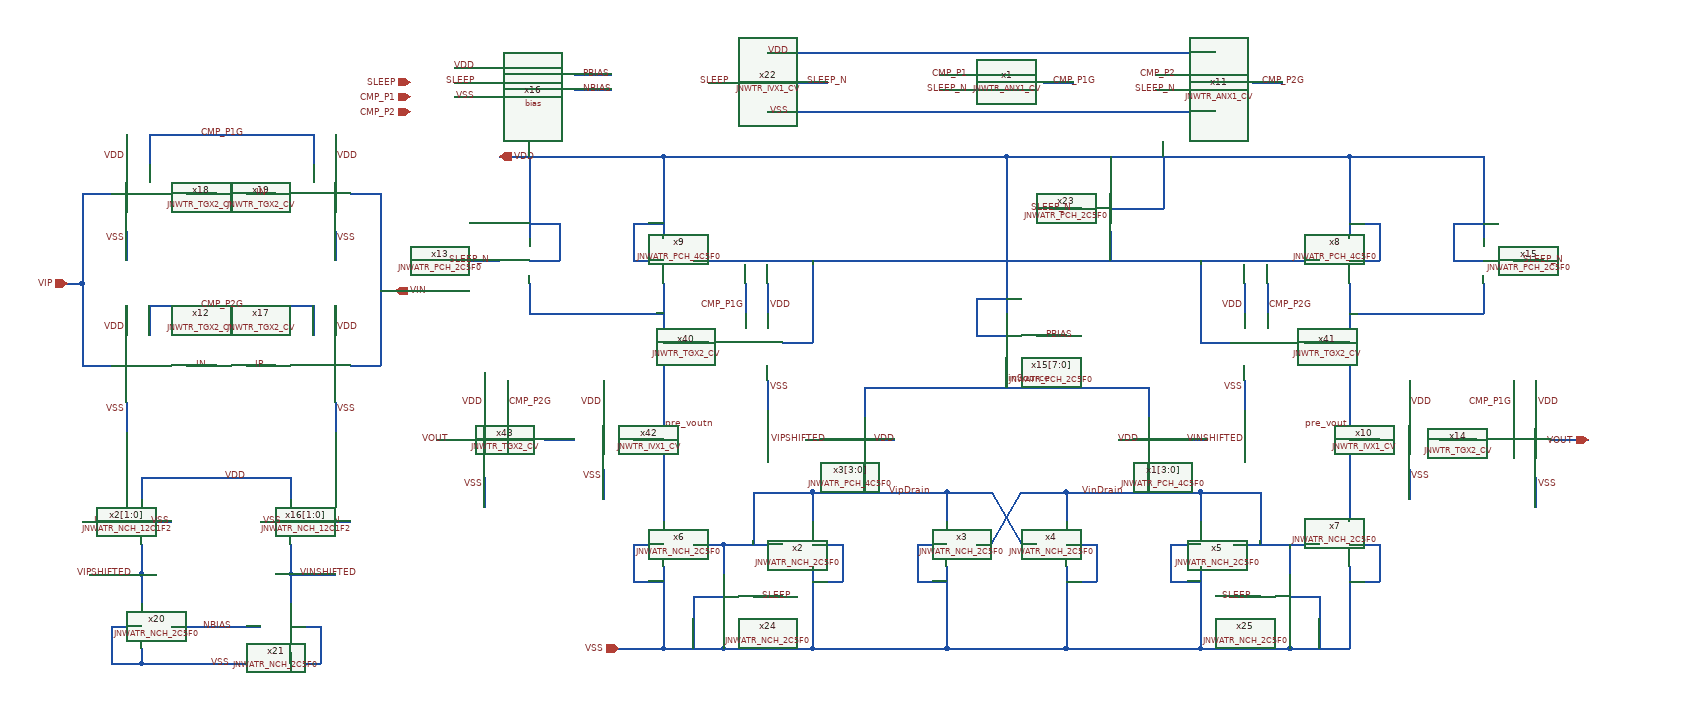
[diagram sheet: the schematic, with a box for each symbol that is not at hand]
v {xschem version=3.4.6 file_version=1.2}
G {}
K {}
V {}
S {}
E {}
N 1240 -550 1240 -510 {
lab=VipDrain}
N 1420 -550 1420 -510 {
lab=VipDrain}
N 1580 -550 1580 -510 {
lab=VinDrain}
N 1680 -550 1760 -550 {
lab=VinDrain}
N 1460 -480 1480 -480 {
lab=VinDrain}
N 1480 -480 1520 -550 {
lab=VinDrain}
N 1520 -480 1540 -480 {
lab=VipDrain}
N 1480 -550 1520 -480 {
lab=VipDrain}
N 1420 -550 1480 -550 {
lab=VipDrain}
N 1520 -550 1580 -550 {
lab=VinDrain}
N 1160 -550 1240 -550 {
lab=VipDrain}
N 1160 -550 1160 -480 {
lab=VipDrain}
N 1240 -860 1240 -750 {
lab=#net1}
N 1730 -1000 1960 -1000 {
lab=VDD}
N 1880 -340 1960 -340 {
lab=VSS}
N 1310 -690 1310 -650 {
lab=inSource}
N 1690 -690 1690 -650 {
lab=inSource}
N 2180 -700 2180 -660 {
lab=CMP_P1G}
N 2230 -620 2280 -620 {
lab=VOUT}
N 260 -830 260 -720 {
lab=VIP}
N 260 -950 300 -950 {
lab=VIP}
N 260 -720 300 -720 {
lab=VIP}
N 660 -950 660 -720 {
lab=VIN}
N 620 -950 660 -950 {
lab=VIN}
N 620 -720 660 -720 {
lab=VIN}
N 350 -800 350 -760 {
lab=CMP_P2G}
N 350 -800 570 -800 {
lab=CMP_P2G}
N 570 -800 570 -760 {
lab=CMP_P2G}
N 350 -1030 350 -990 {
lab=CMP_P1G}
N 350 -1030 570 -1030 {
lab=CMP_P1G}
N 570 -1030 570 -990 {
lab=CMP_P1G}
N 1230 -620 1270 -620 {lab=VIPSHIFTED}
N 260 -950 260 -830 {
lab=VIP}
N 1730 -620 1770 -620 {lab=VINSHIFTED}
N 1580 -550 1680 -550 {
lab=VinDrain}
N 1240 -550 1420 -550 {
lab=VipDrain}
N 1540 -760 1580 -760 {lab=PBIAS}
N 1500 -730 1500 -690 {lab=inSource}
N 260 -510 300 -510 {lab=IP}
N 1310 -690 1690 -690 {
lab=inSource}
N 340 -570 540 -570 {lab=VDD}
N 340 -570 340 -540 {lab=VDD}
N 540 -570 540 -540 {lab=VDD}
N 380 -370 500 -370 {lab=NBIAS}
N 580 -510 620 -510 {lab=IN}
N 580 -370 580 -320 {lab=VSS}
N 340 -320 580 -320 {lab=VSS}
N 300 -370 300 -320 {lab=VSS}
N 270 -440 340 -440 {lab=VIPSHIFTED}
N 540 -440 600 -440 {lab=VINSHIFTED}
N 540 -480 540 -440 {lab=VINSHIFTED}
N 340 -480 340 -440 {lab=VIPSHIFTED}
N 540 -440 540 -400 {lab=VINSHIFTED}
N 340 -440 340 -400 {lab=VIPSHIFTED}
N 240 -830 260 -830 {lab=VIP}
N 1100 -1100 1140 -1100 {lab=SLEEP}
N 1220 -1100 1260 -1100 {lab=SLEEP_N}
N 1640 -900 1640 -860 {lab=#net1}
N 1080 -860 1920 -860 {
lab=#net1}
N 1120 -480 1120 -440 {lab=VipDrain}
N 1080 -480 1120 -480 {
lab=VipDrain}
N 1880 -480 1880 -440 {lab=VinDrain}
N 480 -720 520 -720 {lab=IP}
N 480 -950 520 -950 {lab=IN}
N 2080 -620 2130 -620 {lab=#net2}
N 1760 -860 1760 -750 {lab=#net1}
N 1200 -750 1240 -750 {
lab=#net1}
N 1150 -830 1150 -790 {
lab=CMP_P1G}
N 1849.614593087707 -830 1849.614593087707 -790 {
lab=CMP_P2G}
N 1040 -750 1100 -750 {lab=pre_voutn}
N 1900 -750 1960 -750 {lab=pre_vout}
N 1760 -750 1800 -750 {lab=#net1}
N 880 -620 920 -620 {
lab=#net3}
N 830 -700 830 -640 {
lab=CMP_P2G}
N 735 -620 780 -620 {
lab=VOUT}
N 1000 -620 1040 -620 {lab=pre_voutn}
N 1040 -1000 1500 -1000 {
lab=VDD}
N 1500 -1000 1500 -790 {lab=VDD}
N 1040 -1000 1040 -890 {lab=VDD}
N 820 -1000 1040 -1000 {
lab=VDD}
N 1960 -620 2000 -620 {lab=pre_vout}
N 1000 -480 1000 -430 {lab=VSS}
N 980 -340 1040 -340 {
lab=VSS}
N 1040 -340 1120 -340 {
lab=VSS}
N 1080 -410 1080 -340 {lab=VSS}
N 1120 -340 1240 -340 {
lab=VSS}
N 1240 -450 1240 -340 {lab=VSS}
N 1420 -450 1420 -340 {lab=VSS}
N 1240 -340 1420 -340 {
lab=VSS}
N 1420 -340 1580 -340 {
lab=VSS}
N 1760 -450 1760 -340 {lab=VSS}
N 1580 -340 1760 -340 {
lab=VSS}
N 1760 -340 1880 -340 {
lab=VSS}
N 1920 -410 1920 -340 {lab=VSS}
N 1960 -450 1960 -340 {lab=VSS}
N 1710 -1000 1710 -930 {lab=VDD}
N 1640 -1000 1640 -960 {lab=VDD}
N 1500 -1000 1730 -1000 {
lab=VDD}
N 1830 -1100 1870 -1100 {lab=CMP_P2G}
N 1550 -1100 1590 -1100 {lab=CMP_P1G}
N 1410 -1110 1460 -1110 {lab=CMP_P1}
N 1410 -1090 1460 -1090 {lab=SLEEP_N}
N 1700 -1090 1740 -1090 {lab=SLEEP_N}
N 1700 -1110 1740 -1110 {lab=CMP_P2}
N 1180 -1140 1780 -1140 {lab=VDD}
N 1180 -1060 1780 -1060 {lab=VSS}
N 1960 -860 2000 -860 {lab=VDD}
N 1960 -1000 1960 -890 {lab=VDD}
N 1960 -910 2000 -910 {lab=VDD}
N 1960 -790 2140 -790 {lab=pre_vout}
N 1640 -930 1710 -930 {lab=VDD}
N 400 -950 440 -950 {lab=IP}
N 400 -720 440 -720 {lab=IN}
N 320 -900 320 -860 {lab=VSS}
N 320 -1030 320 -990 {lab=VDD}
N 320 -670 320 -630 {lab=VSS}
N 320 -800 320 -760 {lab=VDD}
N 600 -900 600 -860 {lab=VSS}
N 600 -1030 600 -990 {lab=VDD}
N 600 -670 600 -630 {lab=VSS}
N 600 -800 600 -760 {lab=VDD}
N 660 -820 680 -820 {lab=VIN}
N 300 -370 340 -370 {lab=VSS}
N 340 -340 340 -320 {lab=VSS}
N 540 -370 580 -370 {lab=VSS}
N 540 -335 540 -320 {lab=VSS}
N 340 -510 380 -510 {lab=VSS}
N 500 -510 540 -510 {lab=VSS}
N 800 -710 800 -660 {lab=VDD}
N 800 -570 800 -530 {lab=VSS}
N 960 -700 960 -660 {lab=VDD}
N 960 -580 960 -540 {lab=VSS}
N 860 -830 860 -790 {lab=pre_voutn}
N 860 -790 1040 -790 {lab=pre_voutn}
N 860 -1000 860 -890 {lab=VDD}
N 1000 -910 1040 -910 {lab=VDD}
N 1000 -910 1000 -860 {lab=VDD}
N 1000 -860 1040 -860 {lab=VDD}
N 2140 -830 2140 -790 {lab=pre_vout}
N 2140 -1000 2140 -890 {lab=VDD}
N 2000 -910 2000 -860 {lab=VDD}
N 1180 -830 1180 -790 {lab=VDD}
N 1180 -700 1180 -660 {lab=VSS}
N 1819.614593087707 -830 1819.614593087707 -790 {lab=VDD}
N 1819.614593087707 -700 1819.614593087707 -660 {lab=VSS}
N 780 -860 820 -860 {lab=SLEEP_N}
N 1460 -760 1500 -760 {lab=VDD}
N 1460 -810 1460 -760 {lab=VDD}
N 1460 -810 1500 -810 {lab=VDD}
N 2210 -570 2210 -530 {lab=VSS}
N 2210 -700 2210 -660 {lab=VDD}
N 2040 -700 2040 -660 {lab=VDD}
N 2040 -580 2040 -540 {lab=VSS}
N 2180 -860 2220 -860 {lab=SLEEP_N}
N 1560 -930 1600 -930 {lab=SLEEP_N}
N 1880 -410 1920 -410 {lab=VSS}
N 1880 -380 1880 -340 {lab=VSS}
N 1080 -410 1120 -410 {lab=VSS}
N 1120 -380 1120 -340 {lab=VSS}
N 1240 -480 1280 -480 {lab=VSS}
N 1280 -480 1280 -430 {lab=VSS}
N 1240 -430 1280 -430 {lab=VSS}
N 1380 -430 1420 -430 {lab=VSS}
N 1380 -480 1380 -430 {lab=VSS}
N 1380 -480 1420 -480 {lab=VSS}
N 1580 -430 1620 -430 {lab=VSS}
N 1620 -480 1620 -430 {lab=VSS}
N 1580 -480 1620 -480 {lab=VSS}
N 1760 -550 1760 -510 {lab=VinDrain}
N 1720 -480 1760 -480 {lab=VSS}
N 1720 -480 1720 -430 {lab=VSS}
N 1720 -430 1760 -430 {lab=VSS}
N 1805 -480 1920 -480 {lab=VinDrain}
N 1120 -480 1200 -480 {lab=VipDrain}
N 1760 -550 1840 -550 {lab=VinDrain}
N 1840 -550 1840 -480 {lab=VinDrain}
N 1310 -590 1310 -550 {lab=VipDrain}
N 1690 -590 1690 -550 {lab=VinDrain}
N 1000 -480 1040 -480 {lab=VSS}
N 1040 -450 1040 -340 {lab=VSS}
N 1800 -410 1840 -410 {lab=SLEEP}
N 1160 -410 1200 -410 {lab=SLEEP}
N 1310 -620 1350 -620 {lab=VDD}
N 1650 -620 1690 -620 {lab=VDD}
N 1960 -830 1960 -510 {lab=pre_vout}
N 1040 -830 1040 -510 {lab=pre_voutn}
N 1960 -480 2000 -480 {lab=VSS}
N 2000 -480 2000 -430 {lab=VSS}
N 1960 -430 2000 -430 {lab=VSS}
N 1000 -430 1040 -430 {lab=VSS}
N 1960 -1000 2140 -1000 {lab=VDD}
N 2100 -860 2140 -860 {lab=VDD}
N 2100 -910 2100 -860 {lab=VDD}
N 2100 -910 2140 -910 {lab=VDD}
N 860 -860 900 -860 {lab=VDD}
N 900 -910 900 -860 {lab=VDD}
N 860 -910 900 -910 {lab=VDD}
N 1580 -450 1580 -340 {lab=VSS}
N 300 -320 340 -320 {lab=VSS}
N 920 -1110 970 -1110 {lab=PBIAS}
N 920 -1090 970 -1090 {lab=NBIAS}
N 760 -1120 800 -1120 {lab=VDD}
N 760 -1100 800 -1100 {lab=SLEEP}
N 760 -1080 800 -1080 {lab=VSS}
C {devices/ipin.sym} 980 -340 0 0 {name=p2 lab=VSS
}
C {devices/ipin.sym} 820 -1000 2 1 {name=p3 lab=VDD
}
C {devices/ipin.sym} 680 -820 0 1 {name=p5 lab=VIN
}
C {devices/ipin.sym} 240 -830 0 0 {name=p6 lab=VIP
}
C {JNW_ATR_SKY130A/JNWATR_NCH_2C5F0.sym} 1200 -480 0 0 {name=x2 }
C {JNW_ATR_SKY130A/JNWATR_NCH_2C5F0.sym} 1460 -480 0 1 {name=x3 }
C {JNW_ATR_SKY130A/JNWATR_NCH_2C5F0.sym} 1540 -480 0 0 {name=x4 }
C {JNW_ATR_SKY130A/JNWATR_NCH_2C5F0.sym} 1800 -480 0 1 {name=x5 }
C {JNW_ATR_SKY130A/JNWATR_NCH_2C5F0.sym} 1080 -480 0 1 {name=x6 }
C {JNW_ATR_SKY130A/JNWATR_NCH_2C5F0.sym} 1920 -480 0 0 {name=x7 }
C {JNW_ATR_SKY130A/JNWATR_PCH_4C5F0.sym} 1920 -860 0 0 {name=x8 }
C {JNW_ATR_SKY130A/JNWATR_PCH_4C5F0.sym} 1080 -860 0 1 {name=x9 }
C {devices/opin.sym} 2280 -620 2 1 {name=p7 lab=VOUT}
C {JNW_TR_SKY130A/JNWTR_IVX1_CV.sym} 2000 -620 0 0 {name=x10 }
C {devices/ipin.sym} 700 -1060 0 0 {name=p10 lab=CMP_P2
}
C {devices/lab_wire.sym} 2040 -570 2 0 {name=p19 sig_type=std_logic lab=VSS}
C {JNW_TR_SKY130A/JNWTR_TGX2_CV.sym} 2120 -620 0 0 {name=x14 }
C {devices/lab_wire.sym} 2210 -670 0 1 {name=p20 sig_type=std_logic lab=VDD}
C {devices/lab_wire.sym} 2210 -560 2 0 {name=p21 sig_type=std_logic lab=VSS}
C {devices/lab_wire.sym} 410 -720 0 1 {name=p32 sig_type=std_logic lab=IN}
C {devices/lab_wire.sym} 410 -950 0 1 {name=p33 sig_type=std_logic lab=IP}
C {devices/lab_wire.sym} 290 -510 0 0 {name=p34 sig_type=std_logic lab=IP}
C {devices/lab_wire.sym} 590 -510 0 1 {name=p35 sig_type=std_logic lab=IN}
C {devices/ipin.sym} 700 -1080 0 0 {name=p11 lab=CMP_P1
}
C {devices/lab_wire.sym} 1660 -550 0 0 {name=p12 sig_type=std_logic lab=VinDrain}
C {devices/lab_wire.sym} 1340 -550 0 1 {name=p13 sig_type=std_logic lab=VipDrain}
C {devices/lab_wire.sym} 1040 -640 0 1 {name=p37 sig_type=std_logic lab=pre_voutn}
C {devices/lab_wire.sym} 1960 -640 0 0 {name=p38 sig_type=std_logic lab=pre_vout}
C {JNW_TR_SKY130A/JNWTR_TGX2_CV.sym} 410 -720 0 1 {name=x12 }
C {devices/lab_wire.sym} 320 -770 0 0 {name=p29 sig_type=std_logic lab=VDD}
C {devices/lab_wire.sym} 320 -660 2 1 {name=p30 sig_type=std_logic lab=VSS}
C {JNW_TR_SKY130A/JNWTR_TGX2_CV.sym} 510 -720 0 0 {name=x17 }
C {devices/lab_wire.sym} 600 -770 0 1 {name=p31 sig_type=std_logic lab=VDD}
C {devices/lab_wire.sym} 600 -660 2 0 {name=p36 sig_type=std_logic lab=VSS}
C {JNW_TR_SKY130A/JNWTR_TGX2_CV.sym} 410 -950 0 1 {name=x18 }
C {devices/lab_wire.sym} 320 -1000 0 0 {name=p39 sig_type=std_logic lab=VDD}
C {devices/lab_wire.sym} 320 -890 2 1 {name=p40 sig_type=std_logic lab=VSS}
C {JNW_TR_SKY130A/JNWTR_TGX2_CV.sym} 510 -950 0 0 {name=x19 }
C {devices/lab_wire.sym} 600 -1000 0 1 {name=p41 sig_type=std_logic lab=VDD}
C {devices/lab_wire.sym} 600 -890 2 0 {name=p42 sig_type=std_logic lab=VSS}
C {devices/lab_wire.sym} 490 -720 0 1 {name=p43 sig_type=std_logic lab=IP}
C {devices/lab_wire.sym} 510 -950 0 0 {name=p44 sig_type=std_logic lab=IN}
C {JNW_ATR_SKY130A/JNWATR_PCH_2C5F0.sym} 1540 -760 0 1 {name=x15[7:0]}
C {devices/lab_wire.sym} 1500 -700 0 1 {name=p47 sig_type=std_logic lab=inSource}
C {devices/lab_wire.sym} 2040 -670 0 1 {name=p48 sig_type=std_logic lab=VDD}
C {devices/lab_wire.sym} 1550 -760 0 1 {name=p23 sig_type=std_logic lab=PBIAS}
C {JNW_ATR_SKY130A/JNWATR_NCH_12C1F2.sym} 300 -510 0 0 {name=x2[1:0]}
C {JNW_ATR_SKY130A/JNWATR_NCH_12C1F2.sym} 580 -510 0 1 {name=x16[1:0]}
C {devices/lab_wire.sym} 530 -510 0 0 {name=p14 sig_type=std_logic lab=VSS}
C {devices/lab_wire.sym} 350 -510 0 1 {name=p15 sig_type=std_logic lab=VSS}
C {JNW_ATR_SKY130A/JNWATR_PCH_4C5F0.sym} 1270 -620 0 0 {name=x3[3:0]}
C {devices/lab_wire.sym} 1320 -620 0 1 {name=p4 sig_type=std_logic lab=VDD}
C {devices/lab_wire.sym} 450 -570 0 1 {name=p16 sig_type=std_logic lab=VDD}
C {JNW_ATR_SKY130A/JNWATR_NCH_2C5F0.sym} 380 -370 0 1 {name=x20 }
C {JNW_ATR_SKY130A/JNWATR_NCH_2C5F0.sym} 500 -370 0 0 {name=x21 }
C {devices/lab_wire.sym} 430 -320 0 1 {name=p17 sig_type=std_logic lab=VSS}
C {devices/lab_wire.sym} 420 -370 0 1 {name=p24 sig_type=std_logic lab=NBIAS}
C {devices/lab_wire.sym} 330 -440 0 0 {name=p25 sig_type=std_logic lab=VIPSHIFTED}
C {devices/lab_wire.sym} 550 -440 0 1 {name=p26 sig_type=std_logic lab=VINSHIFTED}
C {JNW_ATR_SKY130A/JNWATR_PCH_4C5F0.sym} 1730 -620 0 1 {name=x1[3:0]}
C {JNW_TR_SKY130A/JNWTR_IVX1_CV.sym} 1140 -1100 0 0 {name=x22 }
C {devices/lab_wire.sym} 1230 -1100 0 1 {name=p50 sig_type=std_logic lab=SLEEP_N}
C {devices/lab_wire.sym} 1130 -1100 0 0 {name=p55 sig_type=std_logic lab=SLEEP}
C {devices/lab_wire.sym} 1210 -1060 2 1 {name=p56 sig_type=std_logic lab=VSS}
C {devices/lab_wire.sym} 1210 -1140 0 0 {name=p57 sig_type=std_logic lab=VDD}
C {JNW_ATR_SKY130A/JNWATR_PCH_2C5F0.sym} 1600 -930 0 0 {name=x23 }
C {devices/lab_wire.sym} 1590 -930 0 0 {name=p58 sig_type=std_logic lab=SLEEP_N}
C {JNW_ATR_SKY130A/JNWATR_NCH_2C5F0.sym} 1160 -410 0 1 {name=x24 }
C {devices/lab_wire.sym} 1170 -410 0 1 {name=p59 sig_type=std_logic lab=SLEEP}
C {JNW_ATR_SKY130A/JNWATR_NCH_2C5F0.sym} 1840 -410 0 0 {name=x25 }
C {devices/lab_wire.sym} 1830 -410 0 0 {name=p60 sig_type=std_logic lab=SLEEP}
C {devices/ipin.sym} 700 -1100 0 0 {name=p61 lab=SLEEP
}
C {JNW_TR_SKY130A/JNWTR_TGX2_CV.sym} 1090 -750 0 0 {name=x40 }
C {devices/lab_wire.sym} 1180 -690 2 0 {name=p66 sig_type=std_logic lab=VSS}
C {JNW_TR_SKY130A/JNWTR_TGX2_CV.sym} 1909.614593087707 -750 0 1 {name=x41 }
C {devices/lab_wire.sym} 1819.614593087707 -800 0 0 {name=p88 sig_type=std_logic lab=VDD}
C {devices/lab_wire.sym} 1819.614593087707 -690 2 1 {name=p96 sig_type=std_logic lab=VSS}
C {JNW_TR_SKY130A/JNWTR_IVX1_CV.sym} 1000 -620 0 1 {name=x42 }
C {devices/lab_wire.sym} 960 -670 0 0 {name=p98 sig_type=std_logic lab=VDD}
C {devices/lab_wire.sym} 960 -570 2 1 {name=p99 sig_type=std_logic lab=VSS}
C {JNW_TR_SKY130A/JNWTR_TGX2_CV.sym} 890 -620 0 1 {name=x43 }
C {devices/lab_wire.sym} 800 -670 0 0 {name=p100 sig_type=std_logic lab=VDD}
C {devices/lab_wire.sym} 800 -560 2 1 {name=p101 sig_type=std_logic lab=VSS}
C {devices/lab_wire.sym} 755 -620 0 0 {name=p103 sig_type=std_logic lab=VOUT}
C {JNW_TR_SKY130A/JNWTR_ANX1_CV.sym} 1460 -1090 0 0 {name=x1 }
C {JNW_TR_SKY130A/JNWTR_ANX1_CV.sym} 1740 -1090 0 0 {name=x11 }
C {devices/lab_wire.sym} 1450 -1090 0 0 {name=p18 sig_type=std_logic lab=SLEEP_N}
C {devices/lab_wire.sym} 1730 -1090 0 0 {name=p49 sig_type=std_logic lab=SLEEP_N}
C {devices/lab_wire.sym} 1450 -1110 0 0 {name=p51 sig_type=std_logic lab=CMP_P1}
C {devices/lab_wire.sym} 1730 -1110 0 0 {name=p52 sig_type=std_logic lab=CMP_P2}
C {devices/lab_wire.sym} 1840 -1100 0 1 {name=p53 sig_type=std_logic lab=CMP_P2G}
C {devices/lab_wire.sym} 1560 -1100 0 1 {name=p54 sig_type=std_logic lab=CMP_P1G}
C {devices/lab_wire.sym} 830 -670 0 1 {name=p46 sig_type=std_logic lab=CMP_P2G}
C {devices/lab_wire.sym} 1849.614593087707 -800 0 1 {name=p62 sig_type=std_logic lab=CMP_P2G}
C {devices/lab_wire.sym} 1150 -800 0 0 {name=p64 sig_type=std_logic lab=CMP_P1G}
C {devices/lab_wire.sym} 2180 -670 0 0 {name=p22 sig_type=std_logic lab=CMP_P1G}
C {JNW_ATR_SKY130A/JNWATR_PCH_2C5F0.sym} 820 -860 0 0 {name=x13 }
C {JNW_ATR_SKY130A/JNWATR_PCH_2C5F0.sym} 2180 -860 0 1 {name=x15 }
C {devices/lab_wire.sym} 810 -860 0 0 {name=p67 sig_type=std_logic lab=SLEEP_N}
C {devices/lab_wire.sym} 2190 -860 0 1 {name=p68 sig_type=std_logic lab=SLEEP_N}
C {devices/lab_wire.sym} 480 -800 0 0 {name=p69 sig_type=std_logic lab=CMP_P2G}
C {devices/lab_wire.sym} 480 -1030 0 0 {name=p70 sig_type=std_logic lab=CMP_P1G}
C {devices/lab_wire.sym} 1180 -800 0 1 {name=p45 sig_type=std_logic lab=VDD}
C {devices/lab_wire.sym} 1680 -620 0 0 {name=p8 sig_type=std_logic lab=VDD}
C {LELO_TORD_SKY130A/bias.sym} 860 -1100 0 0 {name=x16}
C {devices/lab_wire.sym} 930 -1110 0 1 {name=p1 sig_type=std_logic lab=PBIAS}
C {devices/lab_wire.sym} 930 -1090 0 1 {name=p9 sig_type=std_logic lab=NBIAS}
C {devices/lab_wire.sym} 790 -1120 0 0 {name=p63 sig_type=std_logic lab=VDD}
C {devices/lab_wire.sym} 790 -1100 0 0 {name=p65 sig_type=std_logic lab=SLEEP}
C {devices/lab_wire.sym} 790 -1080 0 0 {name=p71 sig_type=std_logic lab=VSS}
C {devices/lab_wire.sym} 1740 -620 0 1 {name=p72 sig_type=std_logic lab=VINSHIFTED}
C {devices/lab_wire.sym} 1260 -620 0 0 {name=p27 sig_type=std_logic lab=VIPSHIFTED}
